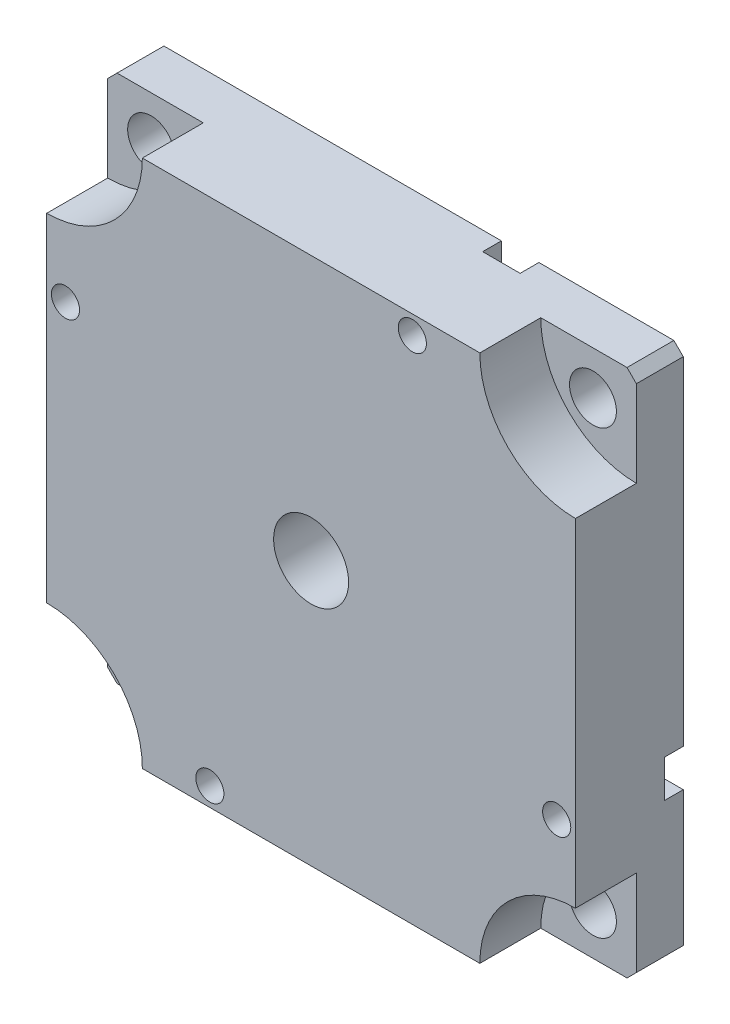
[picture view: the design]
ISO-10303-21;
HEADER;
FILE_DESCRIPTION(('STEP AP214'),'2;1');
FILE_NAME('part.step','',(''),(''),'','','');
FILE_SCHEMA(('AUTOMOTIVE_DESIGN { 1 0 10303 214 1 1 1 1 }'));
ENDSEC;
DATA;
#1=APPLICATION_CONTEXT('core data for automotive mechanical design processes');
#2=APPLICATION_PROTOCOL_DEFINITION('international standard','automotive_design',2000,#1);
#3=PRODUCT_CONTEXT('',#1,'mechanical');
#4=PRODUCT('Part','Part','',(#3));
#5=PRODUCT_RELATED_PRODUCT_CATEGORY('part','',(#4));
#6=PRODUCT_DEFINITION_FORMATION('','',#4);
#7=PRODUCT_DEFINITION_CONTEXT('part definition',#1,'design');
#8=PRODUCT_DEFINITION('design','',#6,#7);
#9=PRODUCT_DEFINITION_SHAPE('','',#8);
#10=(LENGTH_UNIT() NAMED_UNIT(*) SI_UNIT(.MILLI.,.METRE.));
#11=(NAMED_UNIT(*) PLANE_ANGLE_UNIT() SI_UNIT($,.RADIAN.));
#12=(NAMED_UNIT(*) SI_UNIT($,.STERADIAN.) SOLID_ANGLE_UNIT());
#13=UNCERTAINTY_MEASURE_WITH_UNIT(LENGTH_MEASURE(1.E-05),#10,'distance_accuracy_value','');
#14=(GEOMETRIC_REPRESENTATION_CONTEXT(3) GLOBAL_UNCERTAINTY_ASSIGNED_CONTEXT((#13)) GLOBAL_UNIT_ASSIGNED_CONTEXT((#10,
#11,#12)) REPRESENTATION_CONTEXT('',''));
#15=CARTESIAN_POINT('',(0.,0.,0.));
#16=DIRECTION('',(0.,0.,1.));
#17=DIRECTION('',(1.,0.,0.));
#18=AXIS2_PLACEMENT_3D('',#15,#16,#17);
#19=CARTESIAN_POINT('',(0.,0.,5.));
#20=DIRECTION('',(0.,0.,1.));
#21=DIRECTION('',(1.,0.,0.));
#22=AXIS2_PLACEMENT_3D('',#19,#20,#21);
#23=PLANE('',#22);
#24=CARTESIAN_POINT('',(-28.2,28.2,5.));
#25=DIRECTION('',(0.,0.,-1.));
#26=DIRECTION('',(1.,0.,0.));
#27=AXIS2_PLACEMENT_3D('',#24,#25,#26);
#28=CIRCLE('',#27,10.2);
#29=CARTESIAN_POINT('',(-18.,28.2,5.));
#30=VERTEX_POINT('',#29);
#31=CARTESIAN_POINT('',(-28.2,18.,5.));
#32=VERTEX_POINT('',#31);
#33=EDGE_CURVE('E381',#30,#32,#28,.T.);
#34=ORIENTED_EDGE('',*,*,#33,.F.);
#35=DIRECTION('',(-1.,0.,0.));
#36=VECTOR('',#35,1.);
#37=CARTESIAN_POINT('',(27.2,28.2,5.));
#38=LINE('',#37,#36);
#39=CARTESIAN_POINT('',(-27.2,28.2,5.));
#40=VERTEX_POINT('',#39);
#41=EDGE_CURVE('E516',#30,#40,#38,.T.);
#42=ORIENTED_EDGE('',*,*,#41,.T.);
#43=DIRECTION('',(-0.707106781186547,-0.707106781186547,0.));
#44=VECTOR('',#43,1.);
#45=CARTESIAN_POINT('',(-28.2,27.2,5.));
#46=LINE('',#45,#44);
#47=CARTESIAN_POINT('',(-28.2,27.2,5.));
#48=VERTEX_POINT('',#47);
#49=EDGE_CURVE('E484',#40,#48,#46,.T.);
#50=ORIENTED_EDGE('',*,*,#49,.T.);
#51=DIRECTION('',(0.,-1.,0.));
#52=VECTOR('',#51,1.);
#53=CARTESIAN_POINT('',(-28.2,-27.2,5.));
#54=LINE('',#53,#52);
#55=EDGE_CURVE('E462',#48,#32,#54,.T.);
#56=ORIENTED_EDGE('',*,*,#55,.T.);
#57=EDGE_LOOP('',(#34,#42,#50,#56));
#58=FACE_BOUND('',#57,.T.);
#59=CARTESIAN_POINT('',(-23.57,23.57,5.));
#60=DIRECTION('',(0.,0.,-1.));
#61=DIRECTION('',(-1.,0.,0.));
#62=AXIS2_PLACEMENT_3D('',#59,#60,#61);
#63=CIRCLE('',#62,2.5);
#64=CARTESIAN_POINT('',(-26.07,23.57,5.));
#65=VERTEX_POINT('',#64);
#66=EDGE_CURVE('E441',#65,#65,#63,.T.);
#67=ORIENTED_EDGE('',*,*,#66,.T.);
#68=EDGE_LOOP('',(#67));
#69=FACE_BOUND('',#68,.T.);
#70=ADVANCED_FACE('F35',(#58,#69),#23,.T.);
#71=CARTESIAN_POINT('',(28.2,28.2,5.));
#72=DIRECTION('',(0.,0.,-1.));
#73=DIRECTION('',(-1.,0.,0.));
#74=AXIS2_PLACEMENT_3D('',#71,#72,#73);
#75=CIRCLE('',#74,10.2);
#76=CARTESIAN_POINT('',(28.2,18.,5.));
#77=VERTEX_POINT('',#76);
#78=CARTESIAN_POINT('',(18.,28.2,5.));
#79=VERTEX_POINT('',#78);
#80=EDGE_CURVE('E388',#77,#79,#75,.T.);
#81=ORIENTED_EDGE('',*,*,#80,.F.);
#82=DIRECTION('',(0.,1.,0.));
#83=VECTOR('',#82,1.);
#84=CARTESIAN_POINT('',(28.2,-27.2,5.));
#85=LINE('',#84,#83);
#86=CARTESIAN_POINT('',(28.2,27.2,5.));
#87=VERTEX_POINT('',#86);
#88=EDGE_CURVE('E520',#77,#87,#85,.T.);
#89=ORIENTED_EDGE('',*,*,#88,.T.);
#90=DIRECTION('',(-0.707106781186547,0.707106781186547,0.));
#91=VECTOR('',#90,1.);
#92=CARTESIAN_POINT('',(28.2,27.2,5.));
#93=LINE('',#92,#91);
#94=CARTESIAN_POINT('',(27.2,28.2,5.));
#95=VERTEX_POINT('',#94);
#96=EDGE_CURVE('E512',#87,#95,#93,.T.);
#97=ORIENTED_EDGE('',*,*,#96,.T.);
#98=EDGE_CURVE('E509',#95,#79,#38,.T.);
#99=ORIENTED_EDGE('',*,*,#98,.T.);
#100=EDGE_LOOP('',(#81,#89,#97,#99));
#101=FACE_BOUND('',#100,.T.);
#102=CARTESIAN_POINT('',(23.57,23.57,5.));
#103=DIRECTION('',(0.,0.,-1.));
#104=DIRECTION('',(-1.,0.,0.));
#105=AXIS2_PLACEMENT_3D('',#102,#103,#104);
#106=CIRCLE('',#105,2.5);
#107=CARTESIAN_POINT('',(21.07,23.57,5.));
#108=VERTEX_POINT('',#107);
#109=EDGE_CURVE('E447',#108,#108,#106,.T.);
#110=ORIENTED_EDGE('',*,*,#109,.T.);
#111=EDGE_LOOP('',(#110));
#112=FACE_BOUND('',#111,.T.);
#113=ADVANCED_FACE('F658',(#101,#112),#23,.T.);
#114=CARTESIAN_POINT('',(28.2,-28.2,5.));
#115=DIRECTION('',(0.,0.,-1.));
#116=DIRECTION('',(1.,0.,0.));
#117=AXIS2_PLACEMENT_3D('',#114,#115,#116);
#118=CIRCLE('',#117,10.2);
#119=CARTESIAN_POINT('',(18.,-28.2,5.));
#120=VERTEX_POINT('',#119);
#121=CARTESIAN_POINT('',(28.2,-18.,5.));
#122=VERTEX_POINT('',#121);
#123=EDGE_CURVE('E422',#120,#122,#118,.T.);
#124=ORIENTED_EDGE('',*,*,#123,.F.);
#125=DIRECTION('',(1.,0.,0.));
#126=VECTOR('',#125,1.);
#127=CARTESIAN_POINT('',(27.2,-28.2,5.));
#128=LINE('',#127,#126);
#129=CARTESIAN_POINT('',(27.2,-28.2,5.));
#130=VERTEX_POINT('',#129);
#131=EDGE_CURVE('E531',#120,#130,#128,.T.);
#132=ORIENTED_EDGE('',*,*,#131,.T.);
#133=DIRECTION('',(0.707106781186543,0.707106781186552,0.));
#134=VECTOR('',#133,1.);
#135=CARTESIAN_POINT('',(28.2,-27.2,5.));
#136=LINE('',#135,#134);
#137=CARTESIAN_POINT('',(28.2,-27.2,5.));
#138=VERTEX_POINT('',#137);
#139=EDGE_CURVE('E523',#130,#138,#136,.T.);
#140=ORIENTED_EDGE('',*,*,#139,.T.);
#141=EDGE_CURVE('E522',#138,#122,#85,.T.);
#142=ORIENTED_EDGE('',*,*,#141,.T.);
#143=EDGE_LOOP('',(#124,#132,#140,#142));
#144=FACE_BOUND('',#143,.T.);
#145=CARTESIAN_POINT('',(23.57,-23.57,5.));
#146=DIRECTION('',(0.,0.,-1.));
#147=DIRECTION('',(-1.,0.,0.));
#148=AXIS2_PLACEMENT_3D('',#145,#146,#147);
#149=CIRCLE('',#148,2.5);
#150=CARTESIAN_POINT('',(21.07,-23.57,5.));
#151=VERTEX_POINT('',#150);
#152=EDGE_CURVE('E435',#151,#151,#149,.T.);
#153=ORIENTED_EDGE('',*,*,#152,.T.);
#154=EDGE_LOOP('',(#153));
#155=FACE_BOUND('',#154,.T.);
#156=ADVANCED_FACE('F591',(#144,#155),#23,.T.);
#157=CARTESIAN_POINT('',(-28.2,-27.2,5.));
#158=DIRECTION('',(1.,0.,0.));
#159=DIRECTION('',(0.,1.,0.));
#160=AXIS2_PLACEMENT_3D('',#157,#158,#159);
#161=PLANE('',#160);
#162=DIRECTION('',(0.,-1.,0.));
#163=VECTOR('',#162,1.);
#164=CARTESIAN_POINT('',(-28.2,-27.2,0.));
#165=LINE('',#164,#163);
#166=CARTESIAN_POINT('',(-28.2,27.2,0.));
#167=VERTEX_POINT('',#166);
#168=CARTESIAN_POINT('',(-28.1999999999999,12.8000000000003,0.));
#169=VERTEX_POINT('',#168);
#170=EDGE_CURVE('E505',#167,#169,#165,.T.);
#171=ORIENTED_EDGE('',*,*,#170,.T.);
#172=DIRECTION('',(0.,0.,-1.));
#173=VECTOR('',#172,1.);
#174=CARTESIAN_POINT('',(-28.1999999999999,12.8000000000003,2.));
#175=LINE('',#174,#173);
#176=CARTESIAN_POINT('',(-28.1999999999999,12.8000000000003,2.));
#177=VERTEX_POINT('',#176);
#178=EDGE_CURVE('E280',#177,#169,#175,.T.);
#179=ORIENTED_EDGE('',*,*,#178,.F.);
#180=DIRECTION('',(0.,1.,0.));
#181=VECTOR('',#180,1.);
#182=CARTESIAN_POINT('',(-28.1999999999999,12.8000000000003,2.));
#183=LINE('',#182,#181);
#184=CARTESIAN_POINT('',(-28.1999999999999,8.80000000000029,2.));
#185=VERTEX_POINT('',#184);
#186=EDGE_CURVE('E261',#185,#177,#183,.T.);
#187=ORIENTED_EDGE('',*,*,#186,.F.);
#188=DIRECTION('',(0.,0.,-1.));
#189=VECTOR('',#188,1.);
#190=CARTESIAN_POINT('',(-28.1999999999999,8.80000000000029,2.));
#191=LINE('',#190,#189);
#192=CARTESIAN_POINT('',(-28.1999999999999,8.80000000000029,0.));
#193=VERTEX_POINT('',#192);
#194=EDGE_CURVE('E252',#185,#193,#191,.T.);
#195=ORIENTED_EDGE('',*,*,#194,.T.);
#196=CARTESIAN_POINT('',(-28.2,-27.2,0.));
#197=VERTEX_POINT('',#196);
#198=EDGE_CURVE('E450',#193,#197,#165,.T.);
#199=ORIENTED_EDGE('',*,*,#198,.T.);
#200=DIRECTION('',(0.,0.,-1.));
#201=VECTOR('',#200,1.);
#202=CARTESIAN_POINT('',(-28.2,-27.2,5.));
#203=LINE('',#202,#201);
#204=CARTESIAN_POINT('',(-28.2,-27.2,5.));
#205=VERTEX_POINT('',#204);
#206=EDGE_CURVE('E11',#205,#197,#203,.T.);
#207=ORIENTED_EDGE('',*,*,#206,.F.);
#208=CARTESIAN_POINT('',(-28.2,-18.,5.));
#209=VERTEX_POINT('',#208);
#210=EDGE_CURVE('E459',#209,#205,#54,.T.);
#211=ORIENTED_EDGE('',*,*,#210,.F.);
#212=DIRECTION('',(0.,0.,-1.));
#213=VECTOR('',#212,1.);
#214=CARTESIAN_POINT('',(-28.2,-18.,11.5));
#215=LINE('',#214,#213);
#216=CARTESIAN_POINT('',(-28.2,-18.,11.5));
#217=VERTEX_POINT('',#216);
#218=EDGE_CURVE('E557',#217,#209,#215,.T.);
#219=ORIENTED_EDGE('',*,*,#218,.F.);
#220=DIRECTION('',(0.,-1.,0.));
#221=VECTOR('',#220,1.);
#222=CARTESIAN_POINT('',(-28.2,-18.,11.5));
#223=LINE('',#222,#221);
#224=CARTESIAN_POINT('',(-28.2,18.,11.5));
#225=VERTEX_POINT('',#224);
#226=EDGE_CURVE('E387',#225,#217,#223,.T.);
#227=ORIENTED_EDGE('',*,*,#226,.F.);
#228=DIRECTION('',(0.,0.,-1.));
#229=VECTOR('',#228,1.);
#230=CARTESIAN_POINT('',(-28.2,18.,11.5));
#231=LINE('',#230,#229);
#232=EDGE_CURVE('E434',#225,#32,#231,.T.);
#233=ORIENTED_EDGE('',*,*,#232,.T.);
#234=ORIENTED_EDGE('',*,*,#55,.F.);
#235=DIRECTION('',(0.,0.,-1.));
#236=VECTOR('',#235,1.);
#237=CARTESIAN_POINT('',(-28.2,27.2,5.));
#238=LINE('',#237,#236);
#239=EDGE_CURVE('E481',#48,#167,#238,.T.);
#240=ORIENTED_EDGE('',*,*,#239,.T.);
#241=EDGE_LOOP('',(#171,#179,#187,#195,#199,#207,#211,#219,#227,#233,#234,#240));
#242=FACE_BOUND('',#241,.T.);
#243=ADVANCED_FACE('F37',(#242),#161,.F.);
#244=CARTESIAN_POINT('',(-28.2,-27.2,5.));
#245=DIRECTION('',(0.707106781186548,0.707106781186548,0.));
#246=DIRECTION('',(-0.707106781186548,0.707106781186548,0.));
#247=AXIS2_PLACEMENT_3D('',#244,#245,#246);
#248=PLANE('',#247);
#249=DIRECTION('',(0.707106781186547,-0.707106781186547,0.));
#250=VECTOR('',#249,1.);
#251=CARTESIAN_POINT('',(-28.2,-27.2,0.));
#252=LINE('',#251,#250);
#253=CARTESIAN_POINT('',(-27.2,-28.2,0.));
#254=VERTEX_POINT('',#253);
#255=EDGE_CURVE('E503',#197,#254,#252,.T.);
#256=ORIENTED_EDGE('',*,*,#255,.T.);
#257=DIRECTION('',(0.,0.,-1.));
#258=VECTOR('',#257,1.);
#259=CARTESIAN_POINT('',(-27.2,-28.2,5.));
#260=LINE('',#259,#258);
#261=CARTESIAN_POINT('',(-27.2,-28.2,5.));
#262=VERTEX_POINT('',#261);
#263=EDGE_CURVE('E44',#262,#254,#260,.T.);
#264=ORIENTED_EDGE('',*,*,#263,.F.);
#265=DIRECTION('',(0.707106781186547,-0.707106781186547,0.));
#266=VECTOR('',#265,1.);
#267=CARTESIAN_POINT('',(-28.2,-27.2,5.));
#268=LINE('',#267,#266);
#269=EDGE_CURVE('E455',#205,#262,#268,.T.);
#270=ORIENTED_EDGE('',*,*,#269,.F.);
#271=ORIENTED_EDGE('',*,*,#206,.T.);
#272=EDGE_LOOP('',(#256,#264,#270,#271));
#273=FACE_BOUND('',#272,.T.);
#274=ADVANCED_FACE('F545',(#273),#248,.F.);
#275=CARTESIAN_POINT('',(27.2,-28.2,5.));
#276=DIRECTION('',(0.,1.,0.));
#277=DIRECTION('',(-1.,0.,0.));
#278=AXIS2_PLACEMENT_3D('',#275,#276,#277);
#279=PLANE('',#278);
#280=DIRECTION('',(1.,0.,0.));
#281=VECTOR('',#280,1.);
#282=CARTESIAN_POINT('',(27.2,-28.2,0.));
#283=LINE('',#282,#281);
#284=CARTESIAN_POINT('',(-12.8,-28.2,0.));
#285=VERTEX_POINT('',#284);
#286=EDGE_CURVE('E499',#254,#285,#283,.T.);
#287=ORIENTED_EDGE('',*,*,#286,.T.);
#288=DIRECTION('',(0.,0.,-1.));
#289=VECTOR('',#288,1.);
#290=CARTESIAN_POINT('',(-12.8,-28.2,2.));
#291=LINE('',#290,#289);
#292=CARTESIAN_POINT('',(-12.8,-28.2,2.));
#293=VERTEX_POINT('',#292);
#294=EDGE_CURVE('E304',#293,#285,#291,.T.);
#295=ORIENTED_EDGE('',*,*,#294,.F.);
#296=DIRECTION('',(-1.,0.,0.));
#297=VECTOR('',#296,1.);
#298=CARTESIAN_POINT('',(-12.8,-28.2,2.));
#299=LINE('',#298,#297);
#300=CARTESIAN_POINT('',(-8.8,-28.2,2.));
#301=VERTEX_POINT('',#300);
#302=EDGE_CURVE('E290',#301,#293,#299,.T.);
#303=ORIENTED_EDGE('',*,*,#302,.F.);
#304=DIRECTION('',(0.,0.,-1.));
#305=VECTOR('',#304,1.);
#306=CARTESIAN_POINT('',(-8.8,-28.2,2.));
#307=LINE('',#306,#305);
#308=CARTESIAN_POINT('',(-8.8,-28.2,0.));
#309=VERTEX_POINT('',#308);
#310=EDGE_CURVE('E306',#301,#309,#307,.T.);
#311=ORIENTED_EDGE('',*,*,#310,.T.);
#312=CARTESIAN_POINT('',(27.2,-28.2,0.));
#313=VERTEX_POINT('',#312);
#314=EDGE_CURVE('E502',#309,#313,#283,.T.);
#315=ORIENTED_EDGE('',*,*,#314,.T.);
#316=DIRECTION('',(0.,0.,-1.));
#317=VECTOR('',#316,1.);
#318=CARTESIAN_POINT('',(27.2,-28.2,5.));
#319=LINE('',#318,#317);
#320=EDGE_CURVE('E466',#130,#313,#319,.T.);
#321=ORIENTED_EDGE('',*,*,#320,.F.);
#322=ORIENTED_EDGE('',*,*,#131,.F.);
#323=DIRECTION('',(0.,0.,-1.));
#324=VECTOR('',#323,1.);
#325=CARTESIAN_POINT('',(18.,-28.2,11.5));
#326=LINE('',#325,#324);
#327=CARTESIAN_POINT('',(18.,-28.2,11.5));
#328=VERTEX_POINT('',#327);
#329=EDGE_CURVE('E558',#328,#120,#326,.T.);
#330=ORIENTED_EDGE('',*,*,#329,.F.);
#331=DIRECTION('',(1.,0.,0.));
#332=VECTOR('',#331,1.);
#333=CARTESIAN_POINT('',(18.,-28.2,11.5));
#334=LINE('',#333,#332);
#335=CARTESIAN_POINT('',(-18.,-28.2,11.5));
#336=VERTEX_POINT('',#335);
#337=EDGE_CURVE('E392',#336,#328,#334,.T.);
#338=ORIENTED_EDGE('',*,*,#337,.F.);
#339=DIRECTION('',(0.,0.,-1.));
#340=VECTOR('',#339,1.);
#341=CARTESIAN_POINT('',(-18.,-28.2,11.5));
#342=LINE('',#341,#340);
#343=CARTESIAN_POINT('',(-18.,-28.2,5.));
#344=VERTEX_POINT('',#343);
#345=EDGE_CURVE('E553',#336,#344,#342,.T.);
#346=ORIENTED_EDGE('',*,*,#345,.T.);
#347=EDGE_CURVE('E528',#262,#344,#128,.T.);
#348=ORIENTED_EDGE('',*,*,#347,.F.);
#349=ORIENTED_EDGE('',*,*,#263,.T.);
#350=EDGE_LOOP('',(#287,#295,#303,#311,#315,#321,#322,#330,#338,#346,#348,#349));
#351=FACE_BOUND('',#350,.T.);
#352=ADVANCED_FACE('F550',(#351),#279,.F.);
#353=CARTESIAN_POINT('',(28.2,-27.2,5.));
#354=DIRECTION('',(-0.707106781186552,0.707106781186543,0.));
#355=DIRECTION('',(-0.707106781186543,-0.707106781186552,0.));
#356=AXIS2_PLACEMENT_3D('',#353,#354,#355);
#357=PLANE('',#356);
#358=DIRECTION('',(0.707106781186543,0.707106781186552,0.));
#359=VECTOR('',#358,1.);
#360=CARTESIAN_POINT('',(28.2,-27.2,0.));
#361=LINE('',#360,#359);
#362=CARTESIAN_POINT('',(28.2,-27.2,0.));
#363=VERTEX_POINT('',#362);
#364=EDGE_CURVE('E497',#313,#363,#361,.T.);
#365=ORIENTED_EDGE('',*,*,#364,.T.);
#366=DIRECTION('',(0.,0.,-1.));
#367=VECTOR('',#366,1.);
#368=CARTESIAN_POINT('',(28.2,-27.2,5.));
#369=LINE('',#368,#367);
#370=EDGE_CURVE('E469',#138,#363,#369,.T.);
#371=ORIENTED_EDGE('',*,*,#370,.F.);
#372=ORIENTED_EDGE('',*,*,#139,.F.);
#373=ORIENTED_EDGE('',*,*,#320,.T.);
#374=EDGE_LOOP('',(#365,#371,#372,#373));
#375=FACE_BOUND('',#374,.T.);
#376=ADVANCED_FACE('F698',(#375),#357,.F.);
#377=CARTESIAN_POINT('',(28.2,-27.2,5.));
#378=DIRECTION('',(-1.,0.,0.));
#379=DIRECTION('',(0.,0.,1.));
#380=AXIS2_PLACEMENT_3D('',#377,#378,#379);
#381=PLANE('',#380);
#382=DIRECTION('',(0.,1.,0.));
#383=VECTOR('',#382,1.);
#384=CARTESIAN_POINT('',(28.2,-27.2,0.));
#385=LINE('',#384,#383);
#386=CARTESIAN_POINT('',(28.2,-12.8000000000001,0.));
#387=VERTEX_POINT('',#386);
#388=EDGE_CURVE('E493',#363,#387,#385,.T.);
#389=ORIENTED_EDGE('',*,*,#388,.T.);
#390=DIRECTION('',(0.,0.,-1.));
#391=VECTOR('',#390,1.);
#392=CARTESIAN_POINT('',(28.2,-12.8000000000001,2.));
#393=LINE('',#392,#391);
#394=CARTESIAN_POINT('',(28.2,-12.8000000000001,2.));
#395=VERTEX_POINT('',#394);
#396=EDGE_CURVE('E331',#395,#387,#393,.T.);
#397=ORIENTED_EDGE('',*,*,#396,.F.);
#398=DIRECTION('',(0.,-1.,0.));
#399=VECTOR('',#398,1.);
#400=CARTESIAN_POINT('',(28.2,-12.8000000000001,2.));
#401=LINE('',#400,#399);
#402=CARTESIAN_POINT('',(28.2,-8.8000000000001,2.));
#403=VERTEX_POINT('',#402);
#404=EDGE_CURVE('E317',#403,#395,#401,.T.);
#405=ORIENTED_EDGE('',*,*,#404,.F.);
#406=DIRECTION('',(0.,0.,-1.));
#407=VECTOR('',#406,1.);
#408=CARTESIAN_POINT('',(28.2,-8.8000000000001,2.));
#409=LINE('',#408,#407);
#410=CARTESIAN_POINT('',(28.2,-8.8000000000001,0.));
#411=VERTEX_POINT('',#410);
#412=EDGE_CURVE('E333',#403,#411,#409,.T.);
#413=ORIENTED_EDGE('',*,*,#412,.T.);
#414=CARTESIAN_POINT('',(28.2,27.2,0.));
#415=VERTEX_POINT('',#414);
#416=EDGE_CURVE('E496',#411,#415,#385,.T.);
#417=ORIENTED_EDGE('',*,*,#416,.T.);
#418=DIRECTION('',(0.,0.,-1.));
#419=VECTOR('',#418,1.);
#420=CARTESIAN_POINT('',(28.2,27.2,5.));
#421=LINE('',#420,#419);
#422=EDGE_CURVE('E472',#87,#415,#421,.T.);
#423=ORIENTED_EDGE('',*,*,#422,.F.);
#424=ORIENTED_EDGE('',*,*,#88,.F.);
#425=DIRECTION('',(0.,0.,-1.));
#426=VECTOR('',#425,1.);
#427=CARTESIAN_POINT('',(28.2,18.,11.5));
#428=LINE('',#427,#426);
#429=CARTESIAN_POINT('',(28.2,18.,11.5));
#430=VERTEX_POINT('',#429);
#431=EDGE_CURVE('E605',#430,#77,#428,.T.);
#432=ORIENTED_EDGE('',*,*,#431,.F.);
#433=DIRECTION('',(0.,1.,0.));
#434=VECTOR('',#433,1.);
#435=CARTESIAN_POINT('',(28.2,-18.,11.5));
#436=LINE('',#435,#434);
#437=CARTESIAN_POINT('',(28.2,-18.,11.5));
#438=VERTEX_POINT('',#437);
#439=EDGE_CURVE('E396',#438,#430,#436,.T.);
#440=ORIENTED_EDGE('',*,*,#439,.F.);
#441=DIRECTION('',(0.,0.,-1.));
#442=VECTOR('',#441,1.);
#443=CARTESIAN_POINT('',(28.2,-18.,11.5));
#444=LINE('',#443,#442);
#445=EDGE_CURVE('E563',#438,#122,#444,.T.);
#446=ORIENTED_EDGE('',*,*,#445,.T.);
#447=ORIENTED_EDGE('',*,*,#141,.F.);
#448=ORIENTED_EDGE('',*,*,#370,.T.);
#449=EDGE_LOOP('',(#389,#397,#405,#413,#417,#423,#424,#432,#440,#446,#447,#448));
#450=FACE_BOUND('',#449,.T.);
#451=ADVANCED_FACE('F603',(#450),#381,.F.);
#452=CARTESIAN_POINT('',(28.2,27.2,5.));
#453=DIRECTION('',(-0.707106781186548,-0.707106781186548,0.));
#454=DIRECTION('',(0.707106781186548,-0.707106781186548,0.));
#455=AXIS2_PLACEMENT_3D('',#452,#453,#454);
#456=PLANE('',#455);
#457=DIRECTION('',(-0.707106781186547,0.707106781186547,0.));
#458=VECTOR('',#457,1.);
#459=CARTESIAN_POINT('',(28.2,27.2,0.));
#460=LINE('',#459,#458);
#461=CARTESIAN_POINT('',(27.2,28.2,0.));
#462=VERTEX_POINT('',#461);
#463=EDGE_CURVE('E491',#415,#462,#460,.T.);
#464=ORIENTED_EDGE('',*,*,#463,.T.);
#465=DIRECTION('',(0.,0.,-1.));
#466=VECTOR('',#465,1.);
#467=CARTESIAN_POINT('',(27.2,28.2,5.));
#468=LINE('',#467,#466);
#469=EDGE_CURVE('E475',#95,#462,#468,.T.);
#470=ORIENTED_EDGE('',*,*,#469,.F.);
#471=ORIENTED_EDGE('',*,*,#96,.F.);
#472=ORIENTED_EDGE('',*,*,#422,.T.);
#473=EDGE_LOOP('',(#464,#470,#471,#472));
#474=FACE_BOUND('',#473,.T.);
#475=ADVANCED_FACE('F664',(#474),#456,.F.);
#476=CARTESIAN_POINT('',(27.2,28.2,5.));
#477=DIRECTION('',(0.,-1.,0.));
#478=DIRECTION('',(0.,0.,-1.));
#479=AXIS2_PLACEMENT_3D('',#476,#477,#478);
#480=PLANE('',#479);
#481=DIRECTION('',(-1.,0.,0.));
#482=VECTOR('',#481,1.);
#483=CARTESIAN_POINT('',(27.2,28.2,0.));
#484=LINE('',#483,#482);
#485=CARTESIAN_POINT('',(12.8,28.2,0.));
#486=VERTEX_POINT('',#485);
#487=EDGE_CURVE('E487',#462,#486,#484,.T.);
#488=ORIENTED_EDGE('',*,*,#487,.T.);
#489=DIRECTION('',(0.,0.,-1.));
#490=VECTOR('',#489,1.);
#491=CARTESIAN_POINT('',(12.8,28.2,2.));
#492=LINE('',#491,#490);
#493=CARTESIAN_POINT('',(12.8,28.2,2.));
#494=VERTEX_POINT('',#493);
#495=EDGE_CURVE('E359',#494,#486,#492,.T.);
#496=ORIENTED_EDGE('',*,*,#495,.F.);
#497=DIRECTION('',(1.,0.,0.));
#498=VECTOR('',#497,1.);
#499=CARTESIAN_POINT('',(12.8,28.2,2.));
#500=LINE('',#499,#498);
#501=CARTESIAN_POINT('',(8.8,28.2,2.));
#502=VERTEX_POINT('',#501);
#503=EDGE_CURVE('E345',#502,#494,#500,.T.);
#504=ORIENTED_EDGE('',*,*,#503,.F.);
#505=DIRECTION('',(0.,0.,-1.));
#506=VECTOR('',#505,1.);
#507=CARTESIAN_POINT('',(8.8,28.2,2.));
#508=LINE('',#507,#506);
#509=CARTESIAN_POINT('',(8.8,28.2,0.));
#510=VERTEX_POINT('',#509);
#511=EDGE_CURVE('E361',#502,#510,#508,.T.);
#512=ORIENTED_EDGE('',*,*,#511,.T.);
#513=CARTESIAN_POINT('',(-27.2,28.2,0.));
#514=VERTEX_POINT('',#513);
#515=EDGE_CURVE('E490',#510,#514,#484,.T.);
#516=ORIENTED_EDGE('',*,*,#515,.T.);
#517=DIRECTION('',(0.,0.,-1.));
#518=VECTOR('',#517,1.);
#519=CARTESIAN_POINT('',(-27.2,28.2,5.));
#520=LINE('',#519,#518);
#521=EDGE_CURVE('E478',#40,#514,#520,.T.);
#522=ORIENTED_EDGE('',*,*,#521,.F.);
#523=ORIENTED_EDGE('',*,*,#41,.F.);
#524=DIRECTION('',(0.,0.,-1.));
#525=VECTOR('',#524,1.);
#526=CARTESIAN_POINT('',(-18.,28.2,11.5));
#527=LINE('',#526,#525);
#528=CARTESIAN_POINT('',(-18.,28.2,11.5));
#529=VERTEX_POINT('',#528);
#530=EDGE_CURVE('E402',#529,#30,#527,.T.);
#531=ORIENTED_EDGE('',*,*,#530,.F.);
#532=DIRECTION('',(-1.,0.,0.));
#533=VECTOR('',#532,1.);
#534=CARTESIAN_POINT('',(18.,28.2,11.5));
#535=LINE('',#534,#533);
#536=CARTESIAN_POINT('',(18.,28.2,11.5));
#537=VERTEX_POINT('',#536);
#538=EDGE_CURVE('E400',#537,#529,#535,.T.);
#539=ORIENTED_EDGE('',*,*,#538,.F.);
#540=DIRECTION('',(0.,0.,-1.));
#541=VECTOR('',#540,1.);
#542=CARTESIAN_POINT('',(18.,28.2,11.5));
#543=LINE('',#542,#541);
#544=EDGE_CURVE('E416',#537,#79,#543,.T.);
#545=ORIENTED_EDGE('',*,*,#544,.T.);
#546=ORIENTED_EDGE('',*,*,#98,.F.);
#547=ORIENTED_EDGE('',*,*,#469,.T.);
#548=EDGE_LOOP('',(#488,#496,#504,#512,#516,#522,#523,#531,#539,#545,#546,#547));
#549=FACE_BOUND('',#548,.T.);
#550=ADVANCED_FACE('F583',(#549),#480,.F.);
#551=CARTESIAN_POINT('',(-28.2,27.2,5.));
#552=DIRECTION('',(0.707106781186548,-0.707106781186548,0.));
#553=DIRECTION('',(0.707106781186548,0.707106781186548,0.));
#554=AXIS2_PLACEMENT_3D('',#551,#552,#553);
#555=PLANE('',#554);
#556=DIRECTION('',(-0.707106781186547,-0.707106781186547,0.));
#557=VECTOR('',#556,1.);
#558=CARTESIAN_POINT('',(-28.2,27.2,0.));
#559=LINE('',#558,#557);
#560=EDGE_CURVE('E485',#514,#167,#559,.T.);
#561=ORIENTED_EDGE('',*,*,#560,.T.);
#562=ORIENTED_EDGE('',*,*,#239,.F.);
#563=ORIENTED_EDGE('',*,*,#49,.F.);
#564=ORIENTED_EDGE('',*,*,#521,.T.);
#565=EDGE_LOOP('',(#561,#562,#563,#564));
#566=FACE_BOUND('',#565,.T.);
#567=ADVANCED_FACE('F686',(#566),#555,.F.);
#568=CARTESIAN_POINT('',(-28.2,-28.2,5.));
#569=DIRECTION('',(0.,0.,-1.));
#570=DIRECTION('',(-1.,0.,0.));
#571=AXIS2_PLACEMENT_3D('',#568,#569,#570);
#572=CIRCLE('',#571,10.2);
#573=EDGE_CURVE('E411',#209,#344,#572,.T.);
#574=ORIENTED_EDGE('',*,*,#573,.F.);
#575=ORIENTED_EDGE('',*,*,#210,.T.);
#576=ORIENTED_EDGE('',*,*,#269,.T.);
#577=ORIENTED_EDGE('',*,*,#347,.T.);
#578=EDGE_LOOP('',(#574,#575,#576,#577));
#579=FACE_BOUND('',#578,.T.);
#580=CARTESIAN_POINT('',(-23.57,-23.57,5.));
#581=DIRECTION('',(0.,0.,-1.));
#582=DIRECTION('',(-1.,0.,0.));
#583=AXIS2_PLACEMENT_3D('',#580,#581,#582);
#584=CIRCLE('',#583,2.5);
#585=CARTESIAN_POINT('',(-26.07,-23.57,5.));
#586=VERTEX_POINT('',#585);
#587=EDGE_CURVE('E427',#586,#586,#584,.T.);
#588=ORIENTED_EDGE('',*,*,#587,.T.);
#589=EDGE_LOOP('',(#588));
#590=FACE_BOUND('',#589,.T.);
#591=ADVANCED_FACE('F540',(#579,#590),#23,.T.);
#592=CARTESIAN_POINT('',(0.,0.,0.));
#593=DIRECTION('',(0.,0.,1.));
#594=DIRECTION('',(1.,0.,0.));
#595=AXIS2_PLACEMENT_3D('',#592,#593,#594);
#596=PLANE('',#595);
#597=CARTESIAN_POINT('',(0.,0.,0.));
#598=DIRECTION('',(0.,0.,-1.));
#599=DIRECTION('',(-1.,0.,0.));
#600=AXIS2_PLACEMENT_3D('',#597,#598,#599);
#601=CIRCLE('',#600,19.55);
#602=CARTESIAN_POINT('',(-19.55,0.,0.));
#603=VERTEX_POINT('',#602);
#604=EDGE_CURVE('E377',#603,#603,#601,.T.);
#605=ORIENTED_EDGE('',*,*,#604,.F.);
#606=EDGE_LOOP('',(#605));
#607=FACE_BOUND('',#606,.T.);
#608=CARTESIAN_POINT('',(-23.57,-23.57,0.));
#609=DIRECTION('',(0.,0.,-1.));
#610=DIRECTION('',(-1.,0.,0.));
#611=AXIS2_PLACEMENT_3D('',#608,#609,#610);
#612=CIRCLE('',#611,2.5);
#613=CARTESIAN_POINT('',(-26.07,-23.57,0.));
#614=VERTEX_POINT('',#613);
#615=EDGE_CURVE('E431',#614,#614,#612,.T.);
#616=ORIENTED_EDGE('',*,*,#615,.F.);
#617=EDGE_LOOP('',(#616));
#618=FACE_BOUND('',#617,.T.);
#619=CARTESIAN_POINT('',(23.57,-23.57,0.));
#620=DIRECTION('',(0.,0.,-1.));
#621=DIRECTION('',(-1.,0.,0.));
#622=AXIS2_PLACEMENT_3D('',#619,#620,#621);
#623=CIRCLE('',#622,2.5);
#624=CARTESIAN_POINT('',(21.07,-23.57,0.));
#625=VERTEX_POINT('',#624);
#626=EDGE_CURVE('E430',#625,#625,#623,.T.);
#627=ORIENTED_EDGE('',*,*,#626,.F.);
#628=EDGE_LOOP('',(#627));
#629=FACE_BOUND('',#628,.T.);
#630=CARTESIAN_POINT('',(-23.57,23.57,0.));
#631=DIRECTION('',(0.,0.,-1.));
#632=DIRECTION('',(-1.,0.,0.));
#633=AXIS2_PLACEMENT_3D('',#630,#631,#632);
#634=CIRCLE('',#633,2.5);
#635=CARTESIAN_POINT('',(-26.07,23.57,0.));
#636=VERTEX_POINT('',#635);
#637=EDGE_CURVE('E438',#636,#636,#634,.T.);
#638=ORIENTED_EDGE('',*,*,#637,.F.);
#639=EDGE_LOOP('',(#638));
#640=FACE_BOUND('',#639,.T.);
#641=CARTESIAN_POINT('',(23.57,23.57,0.));
#642=DIRECTION('',(0.,0.,-1.));
#643=DIRECTION('',(-1.,0.,0.));
#644=AXIS2_PLACEMENT_3D('',#641,#642,#643);
#645=CIRCLE('',#644,2.5);
#646=CARTESIAN_POINT('',(21.07,23.57,0.));
#647=VERTEX_POINT('',#646);
#648=EDGE_CURVE('E444',#647,#647,#645,.T.);
#649=ORIENTED_EDGE('',*,*,#648,.F.);
#650=EDGE_LOOP('',(#649));
#651=FACE_BOUND('',#650,.T.);
#652=CARTESIAN_POINT('',(-26.1999999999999,10.8000000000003,0.));
#653=DIRECTION('',(0.,0.,-1.));
#654=DIRECTION('',(0.,-1.,0.));
#655=AXIS2_PLACEMENT_3D('',#652,#653,#654);
#656=CIRCLE('',#655,2.);
#657=CARTESIAN_POINT('',(-26.1999999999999,12.8000000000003,0.));
#658=VERTEX_POINT('',#657);
#659=CARTESIAN_POINT('',(-26.1999999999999,8.80000000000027,0.));
#660=VERTEX_POINT('',#659);
#661=EDGE_CURVE('E52',#658,#660,#656,.T.);
#662=ORIENTED_EDGE('',*,*,#661,.F.);
#663=DIRECTION('',(1.,0.,0.));
#664=VECTOR('',#663,1.);
#665=CARTESIAN_POINT('',(-26.1999999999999,12.8000000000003,0.));
#666=LINE('',#665,#664);
#667=EDGE_CURVE('E265',#169,#658,#666,.T.);
#668=ORIENTED_EDGE('',*,*,#667,.F.);
#669=ORIENTED_EDGE('',*,*,#170,.F.);
#670=ORIENTED_EDGE('',*,*,#560,.F.);
#671=ORIENTED_EDGE('',*,*,#515,.F.);
#672=DIRECTION('',(0.,1.,0.));
#673=VECTOR('',#672,1.);
#674=CARTESIAN_POINT('',(8.8,26.2,0.));
#675=LINE('',#674,#673);
#676=CARTESIAN_POINT('',(8.8,26.2,0.));
#677=VERTEX_POINT('',#676);
#678=EDGE_CURVE('E352',#677,#510,#675,.T.);
#679=ORIENTED_EDGE('',*,*,#678,.F.);
#680=CARTESIAN_POINT('',(10.8,26.2,0.));
#681=DIRECTION('',(0.,0.,-1.));
#682=DIRECTION('',(-1.,0.,0.));
#683=AXIS2_PLACEMENT_3D('',#680,#681,#682);
#684=CIRCLE('',#683,2.);
#685=CARTESIAN_POINT('',(12.8,26.2,0.));
#686=VERTEX_POINT('',#685);
#687=EDGE_CURVE('E330',#686,#677,#684,.T.);
#688=ORIENTED_EDGE('',*,*,#687,.F.);
#689=DIRECTION('',(0.,-1.,0.));
#690=VECTOR('',#689,1.);
#691=CARTESIAN_POINT('',(12.8,26.2,0.));
#692=LINE('',#691,#690);
#693=EDGE_CURVE('E342',#486,#686,#692,.T.);
#694=ORIENTED_EDGE('',*,*,#693,.F.);
#695=ORIENTED_EDGE('',*,*,#487,.F.);
#696=ORIENTED_EDGE('',*,*,#463,.F.);
#697=ORIENTED_EDGE('',*,*,#416,.F.);
#698=DIRECTION('',(1.,0.,0.));
#699=VECTOR('',#698,1.);
#700=CARTESIAN_POINT('',(26.2,-8.80000000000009,0.));
#701=LINE('',#700,#699);
#702=CARTESIAN_POINT('',(26.2,-8.80000000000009,0.));
#703=VERTEX_POINT('',#702);
#704=EDGE_CURVE('E324',#703,#411,#701,.T.);
#705=ORIENTED_EDGE('',*,*,#704,.F.);
#706=CARTESIAN_POINT('',(26.2,-10.8000000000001,0.));
#707=DIRECTION('',(0.,0.,-1.));
#708=DIRECTION('',(0.,1.,0.));
#709=AXIS2_PLACEMENT_3D('',#706,#707,#708);
#710=CIRCLE('',#709,2.);
#711=CARTESIAN_POINT('',(26.2,-12.8000000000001,0.));
#712=VERTEX_POINT('',#711);
#713=EDGE_CURVE('E303',#712,#703,#710,.T.);
#714=ORIENTED_EDGE('',*,*,#713,.F.);
#715=DIRECTION('',(-1.,0.,0.));
#716=VECTOR('',#715,1.);
#717=CARTESIAN_POINT('',(26.2,-12.8000000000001,0.));
#718=LINE('',#717,#716);
#719=EDGE_CURVE('E314',#387,#712,#718,.T.);
#720=ORIENTED_EDGE('',*,*,#719,.F.);
#721=ORIENTED_EDGE('',*,*,#388,.F.);
#722=ORIENTED_EDGE('',*,*,#364,.F.);
#723=ORIENTED_EDGE('',*,*,#314,.F.);
#724=DIRECTION('',(0.,-1.,0.));
#725=VECTOR('',#724,1.);
#726=CARTESIAN_POINT('',(-8.8,-26.2,0.));
#727=LINE('',#726,#725);
#728=CARTESIAN_POINT('',(-8.8,-26.2,0.));
#729=VERTEX_POINT('',#728);
#730=EDGE_CURVE('E297',#729,#309,#727,.T.);
#731=ORIENTED_EDGE('',*,*,#730,.F.);
#732=CARTESIAN_POINT('',(-10.8,-26.2,0.));
#733=DIRECTION('',(0.,0.,-1.));
#734=DIRECTION('',(1.,0.,0.));
#735=AXIS2_PLACEMENT_3D('',#732,#733,#734);
#736=CIRCLE('',#735,2.);
#737=CARTESIAN_POINT('',(-12.8,-26.2,0.));
#738=VERTEX_POINT('',#737);
#739=EDGE_CURVE('E60',#738,#729,#736,.T.);
#740=ORIENTED_EDGE('',*,*,#739,.F.);
#741=DIRECTION('',(0.,1.,0.));
#742=VECTOR('',#741,1.);
#743=CARTESIAN_POINT('',(-12.8,-26.2,0.));
#744=LINE('',#743,#742);
#745=EDGE_CURVE('E287',#285,#738,#744,.T.);
#746=ORIENTED_EDGE('',*,*,#745,.F.);
#747=ORIENTED_EDGE('',*,*,#286,.F.);
#748=ORIENTED_EDGE('',*,*,#255,.F.);
#749=ORIENTED_EDGE('',*,*,#198,.F.);
#750=DIRECTION('',(-1.,0.,0.));
#751=VECTOR('',#750,1.);
#752=CARTESIAN_POINT('',(-26.1999999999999,8.80000000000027,0.));
#753=LINE('',#752,#751);
#754=EDGE_CURVE('E268',#660,#193,#753,.T.);
#755=ORIENTED_EDGE('',*,*,#754,.F.);
#756=EDGE_LOOP('',(#662,#668,#669,#670,#671,#679,#688,#694,#695,#696,#697,#705,#714,#720,#721,
#722,#723,#731,#740,#746,#747,#748,#749,#755));
#757=FACE_BOUND('',#756,.T.);
#758=ADVANCED_FACE('F669',(#607,#618,#629,#640,#651,#757),#596,.F.);
#759=CARTESIAN_POINT('',(23.57,23.57,5.));
#760=DIRECTION('',(0.,0.,-1.));
#761=DIRECTION('',(-1.,0.,0.));
#762=AXIS2_PLACEMENT_3D('',#759,#760,#761);
#763=CYLINDRICAL_SURFACE('',#762,2.5);
#764=ORIENTED_EDGE('',*,*,#109,.F.);
#765=EDGE_LOOP('',(#764));
#766=FACE_BOUND('',#765,.T.);
#767=ORIENTED_EDGE('',*,*,#648,.T.);
#768=EDGE_LOOP('',(#767));
#769=FACE_BOUND('',#768,.T.);
#770=ADVANCED_FACE('F738',(#766,#769),#763,.F.);
#771=CARTESIAN_POINT('',(-23.57,23.57,5.));
#772=DIRECTION('',(0.,0.,-1.));
#773=DIRECTION('',(-1.,0.,0.));
#774=AXIS2_PLACEMENT_3D('',#771,#772,#773);
#775=CYLINDRICAL_SURFACE('',#774,2.5);
#776=ORIENTED_EDGE('',*,*,#66,.F.);
#777=EDGE_LOOP('',(#776));
#778=FACE_BOUND('',#777,.T.);
#779=ORIENTED_EDGE('',*,*,#637,.T.);
#780=EDGE_LOOP('',(#779));
#781=FACE_BOUND('',#780,.T.);
#782=ADVANCED_FACE('F784',(#778,#781),#775,.F.);
#783=CARTESIAN_POINT('',(23.57,-23.57,5.));
#784=DIRECTION('',(0.,0.,-1.));
#785=DIRECTION('',(-1.,0.,0.));
#786=AXIS2_PLACEMENT_3D('',#783,#784,#785);
#787=CYLINDRICAL_SURFACE('',#786,2.5);
#788=ORIENTED_EDGE('',*,*,#152,.F.);
#789=EDGE_LOOP('',(#788));
#790=FACE_BOUND('',#789,.T.);
#791=ORIENTED_EDGE('',*,*,#626,.T.);
#792=EDGE_LOOP('',(#791));
#793=FACE_BOUND('',#792,.T.);
#794=ADVANCED_FACE('F794',(#790,#793),#787,.F.);
#795=CARTESIAN_POINT('',(-23.57,-23.57,5.));
#796=DIRECTION('',(0.,0.,-1.));
#797=DIRECTION('',(-1.,0.,0.));
#798=AXIS2_PLACEMENT_3D('',#795,#796,#797);
#799=CYLINDRICAL_SURFACE('',#798,2.5);
#800=ORIENTED_EDGE('',*,*,#587,.F.);
#801=EDGE_LOOP('',(#800));
#802=FACE_BOUND('',#801,.T.);
#803=ORIENTED_EDGE('',*,*,#615,.T.);
#804=EDGE_LOOP('',(#803));
#805=FACE_BOUND('',#804,.T.);
#806=ADVANCED_FACE('F804',(#802,#805),#799,.F.);
#807=CARTESIAN_POINT('',(-28.2,28.2,11.5));
#808=DIRECTION('',(0.,0.,-1.));
#809=DIRECTION('',(-1.,0.,0.));
#810=AXIS2_PLACEMENT_3D('',#807,#808,#809);
#811=CYLINDRICAL_SURFACE('',#810,10.2);
#812=ORIENTED_EDGE('',*,*,#33,.T.);
#813=ORIENTED_EDGE('',*,*,#232,.F.);
#814=CARTESIAN_POINT('',(-28.2,28.2,11.5));
#815=DIRECTION('',(0.,0.,-1.));
#816=DIRECTION('',(1.,0.,0.));
#817=AXIS2_PLACEMENT_3D('',#814,#815,#816);
#818=CIRCLE('',#817,10.2);
#819=EDGE_CURVE('E384',#529,#225,#818,.T.);
#820=ORIENTED_EDGE('',*,*,#819,.F.);
#821=ORIENTED_EDGE('',*,*,#530,.T.);
#822=EDGE_LOOP('',(#812,#813,#820,#821));
#823=FACE_BOUND('',#822,.T.);
#824=ADVANCED_FACE('F576',(#823),#811,.F.);
#825=CARTESIAN_POINT('',(-28.2,-28.2,11.5));
#826=DIRECTION('',(0.,0.,-1.));
#827=DIRECTION('',(-1.,0.,0.));
#828=AXIS2_PLACEMENT_3D('',#825,#826,#827);
#829=CYLINDRICAL_SURFACE('',#828,10.2);
#830=ORIENTED_EDGE('',*,*,#573,.T.);
#831=ORIENTED_EDGE('',*,*,#345,.F.);
#832=CARTESIAN_POINT('',(-28.2,-28.2,11.5));
#833=DIRECTION('',(0.,0.,-1.));
#834=DIRECTION('',(-1.,0.,0.));
#835=AXIS2_PLACEMENT_3D('',#832,#833,#834);
#836=CIRCLE('',#835,10.2);
#837=EDGE_CURVE('E390',#217,#336,#836,.T.);
#838=ORIENTED_EDGE('',*,*,#837,.F.);
#839=ORIENTED_EDGE('',*,*,#218,.T.);
#840=EDGE_LOOP('',(#830,#831,#838,#839));
#841=FACE_BOUND('',#840,.T.);
#842=ADVANCED_FACE('F694',(#841),#829,.F.);
#843=CARTESIAN_POINT('',(28.2,-28.2,11.5));
#844=DIRECTION('',(0.,0.,-1.));
#845=DIRECTION('',(-1.,0.,0.));
#846=AXIS2_PLACEMENT_3D('',#843,#844,#845);
#847=CYLINDRICAL_SURFACE('',#846,10.2);
#848=ORIENTED_EDGE('',*,*,#123,.T.);
#849=ORIENTED_EDGE('',*,*,#445,.F.);
#850=CARTESIAN_POINT('',(28.2,-28.2,11.5));
#851=DIRECTION('',(0.,0.,-1.));
#852=DIRECTION('',(1.,0.,0.));
#853=AXIS2_PLACEMENT_3D('',#850,#851,#852);
#854=CIRCLE('',#853,10.2);
#855=EDGE_CURVE('E394',#328,#438,#854,.T.);
#856=ORIENTED_EDGE('',*,*,#855,.F.);
#857=ORIENTED_EDGE('',*,*,#329,.T.);
#858=EDGE_LOOP('',(#848,#849,#856,#857));
#859=FACE_BOUND('',#858,.T.);
#860=ADVANCED_FACE('F599',(#859),#847,.F.);
#861=CARTESIAN_POINT('',(28.2,28.2,11.5));
#862=DIRECTION('',(0.,0.,-1.));
#863=DIRECTION('',(-1.,0.,0.));
#864=AXIS2_PLACEMENT_3D('',#861,#862,#863);
#865=CYLINDRICAL_SURFACE('',#864,10.2);
#866=ORIENTED_EDGE('',*,*,#80,.T.);
#867=ORIENTED_EDGE('',*,*,#544,.F.);
#868=CARTESIAN_POINT('',(28.2,28.2,11.5));
#869=DIRECTION('',(0.,0.,-1.));
#870=DIRECTION('',(-1.,0.,0.));
#871=AXIS2_PLACEMENT_3D('',#868,#869,#870);
#872=CIRCLE('',#871,10.2);
#873=EDGE_CURVE('E398',#430,#537,#872,.T.);
#874=ORIENTED_EDGE('',*,*,#873,.F.);
#875=ORIENTED_EDGE('',*,*,#431,.T.);
#876=EDGE_LOOP('',(#866,#867,#874,#875));
#877=FACE_BOUND('',#876,.T.);
#878=ADVANCED_FACE('F644',(#877),#865,.F.);
#879=CARTESIAN_POINT('',(-28.2,28.2,11.5));
#880=DIRECTION('',(0.,0.,1.));
#881=DIRECTION('',(1.,0.,0.));
#882=AXIS2_PLACEMENT_3D('',#879,#880,#881);
#883=PLANE('',#882);
#884=CARTESIAN_POINT('',(-26.1999999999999,10.8000000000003,11.5));
#885=DIRECTION('',(0.,0.,1.));
#886=DIRECTION('',(1.,0.,0.));
#887=AXIS2_PLACEMENT_3D('',#884,#885,#886);
#888=CIRCLE('',#887,1.5);
#889=CARTESIAN_POINT('',(-24.6999999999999,10.8000000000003,11.5));
#890=VERTEX_POINT('',#889);
#891=EDGE_CURVE('E624',#890,#890,#888,.T.);
#892=ORIENTED_EDGE('',*,*,#891,.F.);
#893=EDGE_LOOP('',(#892));
#894=FACE_BOUND('',#893,.T.);
#895=CARTESIAN_POINT('',(-10.8,-26.2,11.5));
#896=DIRECTION('',(0.,0.,1.));
#897=DIRECTION('',(1.,0.,0.));
#898=AXIS2_PLACEMENT_3D('',#895,#896,#897);
#899=CIRCLE('',#898,1.5);
#900=CARTESIAN_POINT('',(-9.3,-26.2,11.5));
#901=VERTEX_POINT('',#900);
#902=EDGE_CURVE('E621',#901,#901,#899,.T.);
#903=ORIENTED_EDGE('',*,*,#902,.F.);
#904=EDGE_LOOP('',(#903));
#905=FACE_BOUND('',#904,.T.);
#906=CARTESIAN_POINT('',(26.2,-10.8000000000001,11.5));
#907=DIRECTION('',(0.,0.,1.));
#908=DIRECTION('',(1.,0.,0.));
#909=AXIS2_PLACEMENT_3D('',#906,#907,#908);
#910=CIRCLE('',#909,1.5);
#911=CARTESIAN_POINT('',(27.7,-10.8000000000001,11.5));
#912=VERTEX_POINT('',#911);
#913=EDGE_CURVE('E618',#912,#912,#910,.T.);
#914=ORIENTED_EDGE('',*,*,#913,.F.);
#915=EDGE_LOOP('',(#914));
#916=FACE_BOUND('',#915,.T.);
#917=CARTESIAN_POINT('',(10.8,26.2,11.5));
#918=DIRECTION('',(0.,0.,1.));
#919=DIRECTION('',(1.,0.,0.));
#920=AXIS2_PLACEMENT_3D('',#917,#918,#919);
#921=CIRCLE('',#920,1.5);
#922=CARTESIAN_POINT('',(12.3,26.2,11.5));
#923=VERTEX_POINT('',#922);
#924=EDGE_CURVE('E271',#923,#923,#921,.T.);
#925=ORIENTED_EDGE('',*,*,#924,.F.);
#926=EDGE_LOOP('',(#925));
#927=FACE_BOUND('',#926,.T.);
#928=CARTESIAN_POINT('',(0.,0.,11.5));
#929=DIRECTION('',(0.,0.,1.));
#930=DIRECTION('',(1.,0.,0.));
#931=AXIS2_PLACEMENT_3D('',#928,#929,#930);
#932=CIRCLE('',#931,4.);
#933=CARTESIAN_POINT('',(4.,0.,11.5));
#934=VERTEX_POINT('',#933);
#935=EDGE_CURVE('E368',#934,#934,#932,.T.);
#936=ORIENTED_EDGE('',*,*,#935,.F.);
#937=EDGE_LOOP('',(#936));
#938=FACE_BOUND('',#937,.T.);
#939=ORIENTED_EDGE('',*,*,#819,.T.);
#940=ORIENTED_EDGE('',*,*,#226,.T.);
#941=ORIENTED_EDGE('',*,*,#837,.T.);
#942=ORIENTED_EDGE('',*,*,#337,.T.);
#943=ORIENTED_EDGE('',*,*,#855,.T.);
#944=ORIENTED_EDGE('',*,*,#439,.T.);
#945=ORIENTED_EDGE('',*,*,#873,.T.);
#946=ORIENTED_EDGE('',*,*,#538,.T.);
#947=EDGE_LOOP('',(#939,#940,#941,#942,#943,#944,#945,#946));
#948=FACE_BOUND('',#947,.T.);
#949=ADVANCED_FACE('F640',(#894,#905,#916,#927,#938,#948),#883,.T.);
#950=CARTESIAN_POINT('',(0.,0.,1.));
#951=DIRECTION('',(0.,0.,-1.));
#952=DIRECTION('',(-1.,0.,0.));
#953=AXIS2_PLACEMENT_3D('',#950,#951,#952);
#954=CYLINDRICAL_SURFACE('',#953,19.55);
#955=CARTESIAN_POINT('',(0.,0.,1.));
#956=DIRECTION('',(0.,0.,-1.));
#957=DIRECTION('',(-1.,0.,0.));
#958=AXIS2_PLACEMENT_3D('',#955,#956,#957);
#959=CIRCLE('',#958,19.55);
#960=CARTESIAN_POINT('',(-19.55,0.,1.));
#961=VERTEX_POINT('',#960);
#962=EDGE_CURVE('E378',#961,#961,#959,.T.);
#963=ORIENTED_EDGE('',*,*,#962,.F.);
#964=EDGE_LOOP('',(#963));
#965=FACE_BOUND('',#964,.T.);
#966=ORIENTED_EDGE('',*,*,#604,.T.);
#967=EDGE_LOOP('',(#966));
#968=FACE_BOUND('',#967,.T.);
#969=ADVANCED_FACE('F643',(#965,#968),#954,.F.);
#970=CARTESIAN_POINT('',(0.,0.,1.));
#971=DIRECTION('',(0.,0.,-1.));
#972=DIRECTION('',(-1.,0.,0.));
#973=AXIS2_PLACEMENT_3D('',#970,#971,#972);
#974=PLANE('',#973);
#975=CARTESIAN_POINT('',(0.,0.,1.));
#976=DIRECTION('',(0.,0.,-1.));
#977=DIRECTION('',(-1.,0.,0.));
#978=AXIS2_PLACEMENT_3D('',#975,#976,#977);
#979=CIRCLE('',#978,19.05);
#980=CARTESIAN_POINT('',(-19.05,0.,1.));
#981=VERTEX_POINT('',#980);
#982=EDGE_CURVE('E374',#981,#981,#979,.T.);
#983=ORIENTED_EDGE('',*,*,#982,.F.);
#984=EDGE_LOOP('',(#983));
#985=FACE_BOUND('',#984,.T.);
#986=ORIENTED_EDGE('',*,*,#962,.T.);
#987=EDGE_LOOP('',(#986));
#988=FACE_BOUND('',#987,.T.);
#989=ADVANCED_FACE('F874',(#985,#988),#974,.T.);
#990=CARTESIAN_POINT('',(0.,0.,1.));
#991=DIRECTION('',(0.,0.,-1.));
#992=DIRECTION('',(-1.,0.,0.));
#993=AXIS2_PLACEMENT_3D('',#990,#991,#992);
#994=CYLINDRICAL_SURFACE('',#993,19.05);
#995=ORIENTED_EDGE('',*,*,#982,.T.);
#996=EDGE_LOOP('',(#995));
#997=FACE_BOUND('',#996,.T.);
#998=CARTESIAN_POINT('',(0.,0.,-1.6));
#999=DIRECTION('',(0.,0.,-1.));
#1000=DIRECTION('',(-1.,0.,0.));
#1001=AXIS2_PLACEMENT_3D('',#998,#999,#1000);
#1002=CIRCLE('',#1001,19.05);
#1003=CARTESIAN_POINT('',(-19.05,0.,-1.6));
#1004=VERTEX_POINT('',#1003);
#1005=EDGE_CURVE('E371',#1004,#1004,#1002,.T.);
#1006=ORIENTED_EDGE('',*,*,#1005,.F.);
#1007=EDGE_LOOP('',(#1006));
#1008=FACE_BOUND('',#1007,.T.);
#1009=ADVANCED_FACE('F884',(#997,#1008),#994,.T.);
#1010=CARTESIAN_POINT('',(0.,0.,-1.6));
#1011=DIRECTION('',(0.,0.,-1.));
#1012=DIRECTION('',(-1.,0.,0.));
#1013=AXIS2_PLACEMENT_3D('',#1010,#1011,#1012);
#1014=PLANE('',#1013);
#1015=CARTESIAN_POINT('',(0.,0.,-1.6));
#1016=DIRECTION('',(0.,0.,-1.));
#1017=DIRECTION('',(-1.,0.,0.));
#1018=AXIS2_PLACEMENT_3D('',#1015,#1016,#1017);
#1019=CIRCLE('',#1018,4.);
#1020=CARTESIAN_POINT('',(-4.,0.,-1.6));
#1021=VERTEX_POINT('',#1020);
#1022=EDGE_CURVE('E358',#1021,#1021,#1019,.T.);
#1023=ORIENTED_EDGE('',*,*,#1022,.F.);
#1024=EDGE_LOOP('',(#1023));
#1025=FACE_BOUND('',#1024,.T.);
#1026=ORIENTED_EDGE('',*,*,#1005,.T.);
#1027=EDGE_LOOP('',(#1026));
#1028=FACE_BOUND('',#1027,.T.);
#1029=ADVANCED_FACE('F895',(#1025,#1028),#1014,.T.);
#1030=CARTESIAN_POINT('',(0.,0.,18.4));
#1031=DIRECTION('',(0.,0.,-1.));
#1032=DIRECTION('',(-1.,0.,0.));
#1033=AXIS2_PLACEMENT_3D('',#1030,#1031,#1032);
#1034=CYLINDRICAL_SURFACE('',#1033,4.);
#1035=ORIENTED_EDGE('',*,*,#935,.T.);
#1036=EDGE_LOOP('',(#1035));
#1037=FACE_BOUND('',#1036,.T.);
#1038=ORIENTED_EDGE('',*,*,#1022,.T.);
#1039=EDGE_LOOP('',(#1038));
#1040=FACE_BOUND('',#1039,.T.);
#1041=ADVANCED_FACE('F904',(#1037,#1040),#1034,.F.);
#1042=CARTESIAN_POINT('',(10.8,26.2,2.));
#1043=DIRECTION('',(0.,0.,-1.));
#1044=DIRECTION('',(-1.,0.,0.));
#1045=AXIS2_PLACEMENT_3D('',#1042,#1043,#1044);
#1046=CYLINDRICAL_SURFACE('',#1045,2.);
#1047=ORIENTED_EDGE('',*,*,#687,.T.);
#1048=DIRECTION('',(0.,0.,-1.));
#1049=VECTOR('',#1048,1.);
#1050=CARTESIAN_POINT('',(8.8,26.2,2.));
#1051=LINE('',#1050,#1049);
#1052=CARTESIAN_POINT('',(8.8,26.2,2.));
#1053=VERTEX_POINT('',#1052);
#1054=EDGE_CURVE('E350',#1053,#677,#1051,.T.);
#1055=ORIENTED_EDGE('',*,*,#1054,.F.);
#1056=CARTESIAN_POINT('',(10.8,26.2,2.));
#1057=DIRECTION('',(0.,0.,-1.));
#1058=DIRECTION('',(-1.,0.,0.));
#1059=AXIS2_PLACEMENT_3D('',#1056,#1057,#1058);
#1060=CIRCLE('',#1059,2.);
#1061=CARTESIAN_POINT('',(12.8,26.2,2.));
#1062=VERTEX_POINT('',#1061);
#1063=EDGE_CURVE('E338',#1062,#1053,#1060,.T.);
#1064=ORIENTED_EDGE('',*,*,#1063,.F.);
#1065=DIRECTION('',(0.,0.,-1.));
#1066=VECTOR('',#1065,1.);
#1067=CARTESIAN_POINT('',(12.8,26.2,2.));
#1068=LINE('',#1067,#1066);
#1069=EDGE_CURVE('E356',#1062,#686,#1068,.T.);
#1070=ORIENTED_EDGE('',*,*,#1069,.T.);
#1071=EDGE_LOOP('',(#1047,#1055,#1064,#1070));
#1072=FACE_BOUND('',#1071,.T.);
#1073=ADVANCED_FACE('F913',(#1072),#1046,.F.);
#1074=CARTESIAN_POINT('',(12.8,26.2,2.));
#1075=DIRECTION('',(1.,0.,0.));
#1076=DIRECTION('',(0.,0.,-1.));
#1077=AXIS2_PLACEMENT_3D('',#1074,#1075,#1076);
#1078=PLANE('',#1077);
#1079=ORIENTED_EDGE('',*,*,#693,.T.);
#1080=ORIENTED_EDGE('',*,*,#1069,.F.);
#1081=DIRECTION('',(0.,-1.,0.));
#1082=VECTOR('',#1081,1.);
#1083=CARTESIAN_POINT('',(12.8,26.2,2.));
#1084=LINE('',#1083,#1082);
#1085=EDGE_CURVE('E347',#494,#1062,#1084,.T.);
#1086=ORIENTED_EDGE('',*,*,#1085,.F.);
#1087=ORIENTED_EDGE('',*,*,#495,.T.);
#1088=EDGE_LOOP('',(#1079,#1080,#1086,#1087));
#1089=FACE_BOUND('',#1088,.T.);
#1090=ADVANCED_FACE('F673',(#1089),#1078,.F.);
#1091=CARTESIAN_POINT('',(8.8,26.2,2.));
#1092=DIRECTION('',(-1.,0.,0.));
#1093=DIRECTION('',(0.,0.,1.));
#1094=AXIS2_PLACEMENT_3D('',#1091,#1092,#1093);
#1095=PLANE('',#1094);
#1096=ORIENTED_EDGE('',*,*,#678,.T.);
#1097=ORIENTED_EDGE('',*,*,#511,.F.);
#1098=DIRECTION('',(0.,1.,0.));
#1099=VECTOR('',#1098,1.);
#1100=CARTESIAN_POINT('',(8.8,26.2,2.));
#1101=LINE('',#1100,#1099);
#1102=EDGE_CURVE('E341',#1053,#502,#1101,.T.);
#1103=ORIENTED_EDGE('',*,*,#1102,.F.);
#1104=ORIENTED_EDGE('',*,*,#1054,.T.);
#1105=EDGE_LOOP('',(#1096,#1097,#1103,#1104));
#1106=FACE_BOUND('',#1105,.T.);
#1107=ADVANCED_FACE('F682',(#1106),#1095,.F.);
#1108=CARTESIAN_POINT('',(10.8,26.2,2.));
#1109=DIRECTION('',(0.,0.,-1.));
#1110=DIRECTION('',(-1.,0.,0.));
#1111=AXIS2_PLACEMENT_3D('',#1108,#1109,#1110);
#1112=PLANE('',#1111);
#1113=CARTESIAN_POINT('',(10.8,26.2,2.));
#1114=DIRECTION('',(0.,0.,-1.));
#1115=DIRECTION('',(-1.,0.,0.));
#1116=AXIS2_PLACEMENT_3D('',#1113,#1114,#1115);
#1117=CIRCLE('',#1116,1.5);
#1118=CARTESIAN_POINT('',(9.3,26.2,2.));
#1119=VERTEX_POINT('',#1118);
#1120=EDGE_CURVE('E615',#1119,#1119,#1117,.T.);
#1121=ORIENTED_EDGE('',*,*,#1120,.F.);
#1122=EDGE_LOOP('',(#1121));
#1123=FACE_BOUND('',#1122,.T.);
#1124=ORIENTED_EDGE('',*,*,#1063,.T.);
#1125=ORIENTED_EDGE('',*,*,#1102,.T.);
#1126=ORIENTED_EDGE('',*,*,#503,.T.);
#1127=ORIENTED_EDGE('',*,*,#1085,.T.);
#1128=EDGE_LOOP('',(#1124,#1125,#1126,#1127));
#1129=FACE_BOUND('',#1128,.T.);
#1130=ADVANCED_FACE('F679',(#1123,#1129),#1112,.T.);
#1131=CARTESIAN_POINT('',(26.2,-10.8000000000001,2.));
#1132=DIRECTION('',(0.,0.,-1.));
#1133=DIRECTION('',(-1.,0.,0.));
#1134=AXIS2_PLACEMENT_3D('',#1131,#1132,#1133);
#1135=CYLINDRICAL_SURFACE('',#1134,2.);
#1136=ORIENTED_EDGE('',*,*,#713,.T.);
#1137=DIRECTION('',(0.,0.,-1.));
#1138=VECTOR('',#1137,1.);
#1139=CARTESIAN_POINT('',(26.2,-8.80000000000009,2.));
#1140=LINE('',#1139,#1138);
#1141=CARTESIAN_POINT('',(26.2,-8.80000000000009,2.));
#1142=VERTEX_POINT('',#1141);
#1143=EDGE_CURVE('E322',#1142,#703,#1140,.T.);
#1144=ORIENTED_EDGE('',*,*,#1143,.F.);
#1145=CARTESIAN_POINT('',(26.2,-10.8000000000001,2.));
#1146=DIRECTION('',(0.,0.,-1.));
#1147=DIRECTION('',(0.,1.,0.));
#1148=AXIS2_PLACEMENT_3D('',#1145,#1146,#1147);
#1149=CIRCLE('',#1148,2.);
#1150=CARTESIAN_POINT('',(26.2,-12.8000000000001,2.));
#1151=VERTEX_POINT('',#1150);
#1152=EDGE_CURVE('E310',#1151,#1142,#1149,.T.);
#1153=ORIENTED_EDGE('',*,*,#1152,.F.);
#1154=DIRECTION('',(0.,0.,-1.));
#1155=VECTOR('',#1154,1.);
#1156=CARTESIAN_POINT('',(26.2,-12.8000000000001,2.));
#1157=LINE('',#1156,#1155);
#1158=EDGE_CURVE('E328',#1151,#712,#1157,.T.);
#1159=ORIENTED_EDGE('',*,*,#1158,.T.);
#1160=EDGE_LOOP('',(#1136,#1144,#1153,#1159));
#1161=FACE_BOUND('',#1160,.T.);
#1162=ADVANCED_FACE('F715',(#1161),#1135,.F.);
#1163=CARTESIAN_POINT('',(26.2,-12.8000000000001,2.));
#1164=DIRECTION('',(0.,-1.,0.));
#1165=DIRECTION('',(1.,0.,0.));
#1166=AXIS2_PLACEMENT_3D('',#1163,#1164,#1165);
#1167=PLANE('',#1166);
#1168=ORIENTED_EDGE('',*,*,#719,.T.);
#1169=ORIENTED_EDGE('',*,*,#1158,.F.);
#1170=DIRECTION('',(-1.,0.,0.));
#1171=VECTOR('',#1170,1.);
#1172=CARTESIAN_POINT('',(26.2,-12.8000000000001,2.));
#1173=LINE('',#1172,#1171);
#1174=EDGE_CURVE('E319',#395,#1151,#1173,.T.);
#1175=ORIENTED_EDGE('',*,*,#1174,.F.);
#1176=ORIENTED_EDGE('',*,*,#396,.T.);
#1177=EDGE_LOOP('',(#1168,#1169,#1175,#1176));
#1178=FACE_BOUND('',#1177,.T.);
#1179=ADVANCED_FACE('F705',(#1178),#1167,.F.);
#1180=CARTESIAN_POINT('',(26.2,-8.80000000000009,2.));
#1181=DIRECTION('',(0.,1.,0.));
#1182=DIRECTION('',(-1.,0.,0.));
#1183=AXIS2_PLACEMENT_3D('',#1180,#1181,#1182);
#1184=PLANE('',#1183);
#1185=ORIENTED_EDGE('',*,*,#704,.T.);
#1186=ORIENTED_EDGE('',*,*,#412,.F.);
#1187=DIRECTION('',(1.,0.,0.));
#1188=VECTOR('',#1187,1.);
#1189=CARTESIAN_POINT('',(26.2,-8.80000000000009,2.));
#1190=LINE('',#1189,#1188);
#1191=EDGE_CURVE('E313',#1142,#403,#1190,.T.);
#1192=ORIENTED_EDGE('',*,*,#1191,.F.);
#1193=ORIENTED_EDGE('',*,*,#1143,.T.);
#1194=EDGE_LOOP('',(#1185,#1186,#1192,#1193));
#1195=FACE_BOUND('',#1194,.T.);
#1196=ADVANCED_FACE('F713',(#1195),#1184,.F.);
#1197=CARTESIAN_POINT('',(26.2,-10.8000000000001,2.));
#1198=DIRECTION('',(0.,0.,-1.));
#1199=DIRECTION('',(0.,1.,0.));
#1200=AXIS2_PLACEMENT_3D('',#1197,#1198,#1199);
#1201=PLANE('',#1200);
#1202=CARTESIAN_POINT('',(26.2,-10.8000000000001,2.));
#1203=DIRECTION('',(0.,0.,-1.));
#1204=DIRECTION('',(-1.,0.,0.));
#1205=AXIS2_PLACEMENT_3D('',#1202,#1203,#1204);
#1206=CIRCLE('',#1205,1.5);
#1207=CARTESIAN_POINT('',(24.7,-10.8000000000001,2.));
#1208=VERTEX_POINT('',#1207);
#1209=EDGE_CURVE('E619',#1208,#1208,#1206,.T.);
#1210=ORIENTED_EDGE('',*,*,#1209,.F.);
#1211=EDGE_LOOP('',(#1210));
#1212=FACE_BOUND('',#1211,.T.);
#1213=ORIENTED_EDGE('',*,*,#1152,.T.);
#1214=ORIENTED_EDGE('',*,*,#1191,.T.);
#1215=ORIENTED_EDGE('',*,*,#404,.T.);
#1216=ORIENTED_EDGE('',*,*,#1174,.T.);
#1217=EDGE_LOOP('',(#1213,#1214,#1215,#1216));
#1218=FACE_BOUND('',#1217,.T.);
#1219=ADVANCED_FACE('F710',(#1212,#1218),#1201,.T.);
#1220=CARTESIAN_POINT('',(-10.8,-26.2,2.));
#1221=DIRECTION('',(0.,0.,-1.));
#1222=DIRECTION('',(-1.,0.,0.));
#1223=AXIS2_PLACEMENT_3D('',#1220,#1221,#1222);
#1224=CYLINDRICAL_SURFACE('',#1223,2.);
#1225=ORIENTED_EDGE('',*,*,#739,.T.);
#1226=DIRECTION('',(0.,0.,-1.));
#1227=VECTOR('',#1226,1.);
#1228=CARTESIAN_POINT('',(-8.8,-26.2,2.));
#1229=LINE('',#1228,#1227);
#1230=CARTESIAN_POINT('',(-8.8,-26.2,2.));
#1231=VERTEX_POINT('',#1230);
#1232=EDGE_CURVE('E295',#1231,#729,#1229,.T.);
#1233=ORIENTED_EDGE('',*,*,#1232,.F.);
#1234=CARTESIAN_POINT('',(-10.8,-26.2,2.));
#1235=DIRECTION('',(0.,0.,-1.));
#1236=DIRECTION('',(1.,0.,0.));
#1237=AXIS2_PLACEMENT_3D('',#1234,#1235,#1236);
#1238=CIRCLE('',#1237,2.);
#1239=CARTESIAN_POINT('',(-12.8,-26.2,2.));
#1240=VERTEX_POINT('',#1239);
#1241=EDGE_CURVE('E283',#1240,#1231,#1238,.T.);
#1242=ORIENTED_EDGE('',*,*,#1241,.F.);
#1243=DIRECTION('',(0.,0.,-1.));
#1244=VECTOR('',#1243,1.);
#1245=CARTESIAN_POINT('',(-12.8,-26.2,2.));
#1246=LINE('',#1245,#1244);
#1247=EDGE_CURVE('E301',#1240,#738,#1246,.T.);
#1248=ORIENTED_EDGE('',*,*,#1247,.T.);
#1249=EDGE_LOOP('',(#1225,#1233,#1242,#1248));
#1250=FACE_BOUND('',#1249,.T.);
#1251=ADVANCED_FACE('F975',(#1250),#1224,.F.);
#1252=CARTESIAN_POINT('',(-12.8,-26.2,2.));
#1253=DIRECTION('',(-1.,0.,0.));
#1254=DIRECTION('',(0.,0.,1.));
#1255=AXIS2_PLACEMENT_3D('',#1252,#1253,#1254);
#1256=PLANE('',#1255);
#1257=ORIENTED_EDGE('',*,*,#745,.T.);
#1258=ORIENTED_EDGE('',*,*,#1247,.F.);
#1259=DIRECTION('',(0.,1.,0.));
#1260=VECTOR('',#1259,1.);
#1261=CARTESIAN_POINT('',(-12.8,-26.2,2.));
#1262=LINE('',#1261,#1260);
#1263=EDGE_CURVE('E292',#293,#1240,#1262,.T.);
#1264=ORIENTED_EDGE('',*,*,#1263,.F.);
#1265=ORIENTED_EDGE('',*,*,#294,.T.);
#1266=EDGE_LOOP('',(#1257,#1258,#1264,#1265));
#1267=FACE_BOUND('',#1266,.T.);
#1268=ADVANCED_FACE('F1037',(#1267),#1256,.F.);
#1269=CARTESIAN_POINT('',(-8.8,-26.2,2.));
#1270=DIRECTION('',(1.,0.,0.));
#1271=DIRECTION('',(0.,0.,-1.));
#1272=AXIS2_PLACEMENT_3D('',#1269,#1270,#1271);
#1273=PLANE('',#1272);
#1274=ORIENTED_EDGE('',*,*,#730,.T.);
#1275=ORIENTED_EDGE('',*,*,#310,.F.);
#1276=DIRECTION('',(0.,-1.,0.));
#1277=VECTOR('',#1276,1.);
#1278=CARTESIAN_POINT('',(-8.8,-26.2,2.));
#1279=LINE('',#1278,#1277);
#1280=EDGE_CURVE('E286',#1231,#301,#1279,.T.);
#1281=ORIENTED_EDGE('',*,*,#1280,.F.);
#1282=ORIENTED_EDGE('',*,*,#1232,.T.);
#1283=EDGE_LOOP('',(#1274,#1275,#1281,#1282));
#1284=FACE_BOUND('',#1283,.T.);
#1285=ADVANCED_FACE('F990',(#1284),#1273,.F.);
#1286=CARTESIAN_POINT('',(-10.8,-26.2,2.));
#1287=DIRECTION('',(0.,0.,-1.));
#1288=DIRECTION('',(1.,0.,0.));
#1289=AXIS2_PLACEMENT_3D('',#1286,#1287,#1288);
#1290=PLANE('',#1289);
#1291=CARTESIAN_POINT('',(-10.8,-26.2,2.));
#1292=DIRECTION('',(0.,0.,-1.));
#1293=DIRECTION('',(-1.,0.,0.));
#1294=AXIS2_PLACEMENT_3D('',#1291,#1292,#1293);
#1295=CIRCLE('',#1294,1.5);
#1296=CARTESIAN_POINT('',(-12.3,-26.2,2.));
#1297=VERTEX_POINT('',#1296);
#1298=EDGE_CURVE('E622',#1297,#1297,#1295,.T.);
#1299=ORIENTED_EDGE('',*,*,#1298,.F.);
#1300=EDGE_LOOP('',(#1299));
#1301=FACE_BOUND('',#1300,.T.);
#1302=ORIENTED_EDGE('',*,*,#1241,.T.);
#1303=ORIENTED_EDGE('',*,*,#1280,.T.);
#1304=ORIENTED_EDGE('',*,*,#302,.T.);
#1305=ORIENTED_EDGE('',*,*,#1263,.T.);
#1306=EDGE_LOOP('',(#1302,#1303,#1304,#1305));
#1307=FACE_BOUND('',#1306,.T.);
#1308=ADVANCED_FACE('F985',(#1301,#1307),#1290,.T.);
#1309=CARTESIAN_POINT('',(-26.1999999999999,10.8000000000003,2.));
#1310=DIRECTION('',(0.,0.,-1.));
#1311=DIRECTION('',(-1.,0.,0.));
#1312=AXIS2_PLACEMENT_3D('',#1309,#1310,#1311);
#1313=CYLINDRICAL_SURFACE('',#1312,2.);
#1314=ORIENTED_EDGE('',*,*,#661,.T.);
#1315=DIRECTION('',(0.,0.,-1.));
#1316=VECTOR('',#1315,1.);
#1317=CARTESIAN_POINT('',(-26.1999999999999,8.80000000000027,2.));
#1318=LINE('',#1317,#1316);
#1319=CARTESIAN_POINT('',(-26.1999999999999,8.80000000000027,2.));
#1320=VERTEX_POINT('',#1319);
#1321=EDGE_CURVE('E244',#1320,#660,#1318,.T.);
#1322=ORIENTED_EDGE('',*,*,#1321,.F.);
#1323=CARTESIAN_POINT('',(-26.1999999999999,10.8000000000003,2.));
#1324=DIRECTION('',(0.,0.,-1.));
#1325=DIRECTION('',(0.,-1.,0.));
#1326=AXIS2_PLACEMENT_3D('',#1323,#1324,#1325);
#1327=CIRCLE('',#1326,2.);
#1328=CARTESIAN_POINT('',(-26.1999999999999,12.8000000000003,2.));
#1329=VERTEX_POINT('',#1328);
#1330=EDGE_CURVE('E248',#1329,#1320,#1327,.T.);
#1331=ORIENTED_EDGE('',*,*,#1330,.F.);
#1332=DIRECTION('',(0.,0.,-1.));
#1333=VECTOR('',#1332,1.);
#1334=CARTESIAN_POINT('',(-26.1999999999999,12.8000000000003,2.));
#1335=LINE('',#1334,#1333);
#1336=EDGE_CURVE('E278',#1329,#658,#1335,.T.);
#1337=ORIENTED_EDGE('',*,*,#1336,.T.);
#1338=EDGE_LOOP('',(#1314,#1322,#1331,#1337));
#1339=FACE_BOUND('',#1338,.T.);
#1340=ADVANCED_FACE('F246',(#1339),#1313,.F.);
#1341=CARTESIAN_POINT('',(-26.1999999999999,12.8000000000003,2.));
#1342=DIRECTION('',(0.,1.,0.));
#1343=DIRECTION('',(-1.,0.,0.));
#1344=AXIS2_PLACEMENT_3D('',#1341,#1342,#1343);
#1345=PLANE('',#1344);
#1346=ORIENTED_EDGE('',*,*,#667,.T.);
#1347=ORIENTED_EDGE('',*,*,#1336,.F.);
#1348=DIRECTION('',(1.,0.,0.));
#1349=VECTOR('',#1348,1.);
#1350=CARTESIAN_POINT('',(-26.1999999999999,12.8000000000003,2.));
#1351=LINE('',#1350,#1349);
#1352=EDGE_CURVE('E253',#177,#1329,#1351,.T.);
#1353=ORIENTED_EDGE('',*,*,#1352,.F.);
#1354=ORIENTED_EDGE('',*,*,#178,.T.);
#1355=EDGE_LOOP('',(#1346,#1347,#1353,#1354));
#1356=FACE_BOUND('',#1355,.T.);
#1357=ADVANCED_FACE('F691',(#1356),#1345,.F.);
#1358=CARTESIAN_POINT('',(-26.1999999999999,8.80000000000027,2.));
#1359=DIRECTION('',(0.,-1.,0.));
#1360=DIRECTION('',(1.,0.,0.));
#1361=AXIS2_PLACEMENT_3D('',#1358,#1359,#1360);
#1362=PLANE('',#1361);
#1363=ORIENTED_EDGE('',*,*,#754,.T.);
#1364=ORIENTED_EDGE('',*,*,#194,.F.);
#1365=DIRECTION('',(-1.,0.,0.));
#1366=VECTOR('',#1365,1.);
#1367=CARTESIAN_POINT('',(-26.1999999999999,8.80000000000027,2.));
#1368=LINE('',#1367,#1366);
#1369=EDGE_CURVE('E256',#1320,#185,#1368,.T.);
#1370=ORIENTED_EDGE('',*,*,#1369,.F.);
#1371=ORIENTED_EDGE('',*,*,#1321,.T.);
#1372=EDGE_LOOP('',(#1363,#1364,#1370,#1371));
#1373=FACE_BOUND('',#1372,.T.);
#1374=ADVANCED_FACE('F257',(#1373),#1362,.F.);
#1375=CARTESIAN_POINT('',(-26.1999999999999,10.8000000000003,2.));
#1376=DIRECTION('',(0.,0.,-1.));
#1377=DIRECTION('',(0.,-1.,0.));
#1378=AXIS2_PLACEMENT_3D('',#1375,#1376,#1377);
#1379=PLANE('',#1378);
#1380=CARTESIAN_POINT('',(-26.1999999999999,10.8000000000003,2.));
#1381=DIRECTION('',(0.,0.,-1.));
#1382=DIRECTION('',(-1.,0.,0.));
#1383=AXIS2_PLACEMENT_3D('',#1380,#1381,#1382);
#1384=CIRCLE('',#1383,1.5);
#1385=CARTESIAN_POINT('',(-27.6999999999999,10.8000000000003,2.));
#1386=VERTEX_POINT('',#1385);
#1387=EDGE_CURVE('E39',#1386,#1386,#1384,.T.);
#1388=ORIENTED_EDGE('',*,*,#1387,.F.);
#1389=EDGE_LOOP('',(#1388));
#1390=FACE_BOUND('',#1389,.T.);
#1391=ORIENTED_EDGE('',*,*,#1330,.T.);
#1392=ORIENTED_EDGE('',*,*,#1369,.T.);
#1393=ORIENTED_EDGE('',*,*,#186,.T.);
#1394=ORIENTED_EDGE('',*,*,#1352,.T.);
#1395=EDGE_LOOP('',(#1391,#1392,#1393,#1394));
#1396=FACE_BOUND('',#1395,.T.);
#1397=ADVANCED_FACE('F263',(#1390,#1396),#1379,.T.);
#1398=CARTESIAN_POINT('',(10.8,26.2,50.));
#1399=DIRECTION('',(0.,0.,-1.));
#1400=DIRECTION('',(-1.,0.,0.));
#1401=AXIS2_PLACEMENT_3D('',#1398,#1399,#1400);
#1402=CYLINDRICAL_SURFACE('',#1401,1.5);
#1403=ORIENTED_EDGE('',*,*,#924,.T.);
#1404=EDGE_LOOP('',(#1403));
#1405=FACE_BOUND('',#1404,.T.);
#1406=ORIENTED_EDGE('',*,*,#1120,.T.);
#1407=EDGE_LOOP('',(#1406));
#1408=FACE_BOUND('',#1407,.T.);
#1409=ADVANCED_FACE('F950',(#1405,#1408),#1402,.F.);
#1410=CARTESIAN_POINT('',(26.2,-10.8000000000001,50.));
#1411=DIRECTION('',(0.,0.,-1.));
#1412=DIRECTION('',(-1.,0.,0.));
#1413=AXIS2_PLACEMENT_3D('',#1410,#1411,#1412);
#1414=CYLINDRICAL_SURFACE('',#1413,1.5);
#1415=ORIENTED_EDGE('',*,*,#913,.T.);
#1416=EDGE_LOOP('',(#1415));
#1417=FACE_BOUND('',#1416,.T.);
#1418=ORIENTED_EDGE('',*,*,#1209,.T.);
#1419=EDGE_LOOP('',(#1418));
#1420=FACE_BOUND('',#1419,.T.);
#1421=ADVANCED_FACE('F637',(#1417,#1420),#1414,.F.);
#1422=CARTESIAN_POINT('',(-10.8,-26.2,50.));
#1423=DIRECTION('',(0.,0.,-1.));
#1424=DIRECTION('',(-1.,0.,0.));
#1425=AXIS2_PLACEMENT_3D('',#1422,#1423,#1424);
#1426=CYLINDRICAL_SURFACE('',#1425,1.5);
#1427=ORIENTED_EDGE('',*,*,#902,.T.);
#1428=EDGE_LOOP('',(#1427));
#1429=FACE_BOUND('',#1428,.T.);
#1430=ORIENTED_EDGE('',*,*,#1298,.T.);
#1431=EDGE_LOOP('',(#1430));
#1432=FACE_BOUND('',#1431,.T.);
#1433=ADVANCED_FACE('F1009',(#1429,#1432),#1426,.F.);
#1434=CARTESIAN_POINT('',(-26.1999999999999,10.8000000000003,50.));
#1435=DIRECTION('',(0.,0.,-1.));
#1436=DIRECTION('',(-1.,0.,0.));
#1437=AXIS2_PLACEMENT_3D('',#1434,#1435,#1436);
#1438=CYLINDRICAL_SURFACE('',#1437,1.5);
#1439=ORIENTED_EDGE('',*,*,#891,.T.);
#1440=EDGE_LOOP('',(#1439));
#1441=FACE_BOUND('',#1440,.T.);
#1442=ORIENTED_EDGE('',*,*,#1387,.T.);
#1443=EDGE_LOOP('',(#1442));
#1444=FACE_BOUND('',#1443,.T.);
#1445=ADVANCED_FACE('F1018',(#1441,#1444),#1438,.F.);
#1446=CLOSED_SHELL('',(#70,#113,#156,#243,#274,#352,#376,#451,#475,#550,#567,#591,#758,#770,
#782,#794,#806,#824,#842,#860,#878,#949,#969,#989,#1009,#1029,#1041,#1073,#1090,#1107,#1130,
#1162,#1179,#1196,#1219,#1251,#1268,#1285,#1308,#1340,#1357,#1374,#1397,#1409,#1421,#1433,#1445));
#1447=MANIFOLD_SOLID_BREP('B2',#1446);
#1448=ADVANCED_BREP_SHAPE_REPRESENTATION('',(#18,#1447),#14);
#1449=SHAPE_DEFINITION_REPRESENTATION(#9,#1448);
ENDSEC;
END-ISO-10303-21;
